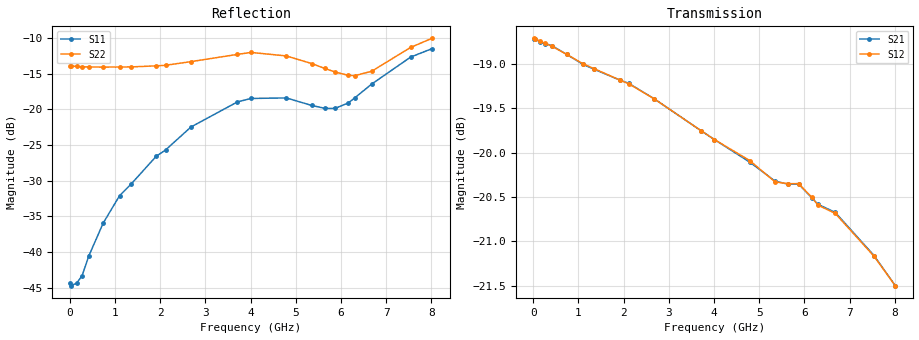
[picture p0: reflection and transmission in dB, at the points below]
! DEVICE ID: PE43712
! File Path: z:\PE43713\PE43713_CHAR_NOM_04292014\AMB\3p300\LS_ATT_17p50dB\PE43713_AMB_3p300V_3p000V_0p000V_LS_ATT_17p50dB_S2P_SN_10_A0139A.s2p
! Serial: 10
! Lot: A0139A
! Temp: 25C
! VDD: 3.300
! VSS: 0.000
! Control_Hi: 3.000
! Control_Lo: 0.000
! Attenuation Step: 17.50dB
! Port 1: RF1
! Port 2: RF2
! ThroughPath:1-2
! IDD: 0.0001465933
! ISS: -1.47e-007
#  Hz  S  RI  R  50
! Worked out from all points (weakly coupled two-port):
!   801 points, 10 MHz to 8.01 GHz, reference 50 ohm
!   highest |S21| = -18.71 dB at 10 MHz (marker M1); lowest = -21.5 dB at 8.01 GHz (marker M2)
!   lowest |S11| = -44.7 dB at 30 MHz (marker M3), VSWR 1.01, Z = 49.4 + j0.136 ohm
!   |S11| at or under -10 dB: start of sweep to end of sweep
!   |S22| runs from -15.3 to -10.0 dB; largest |S21 - S12| = 0.00042
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1e7  -0.00601 0.000558  0.1159 -0.00059  0.116 -0.000561  -0.2019 0.00137
3e7  -0.00564 0.00137  0.1159 -0.00145  0.1159 -0.00147  -0.2013 0.00327
1.5e8  -0.00479 0.0037  0.1153 -0.00683  0.1154 -0.00684  -0.1997 0.0125
2.7e8  -0.0041 0.00542  0.1146 -0.012  0.1146 -0.0121  -0.1981 0.0202
4.2e8  -0.00377 0.00859  0.1134 -0.0184  0.1133 -0.0184  -0.1961 0.0302
7.4e8  -0.00348 0.0156  0.1093 -0.031  0.1093 -0.031  -0.1907 0.0532
1.1e9  -0.00215 0.0247  0.1032 -0.0439  0.1033 -0.0439  -0.1823 0.0781
1.35e9  0.000228 0.0298  0.0985 -0.0521  0.0986 -0.0521  -0.1751 0.0935
1.91e9  0.00883 0.046  0.0857 -0.0688  0.0857 -0.0688  -0.1527 0.1322
2.12e9  0.0128 0.0504  0.0802 -0.0744  0.0802 -0.0743  -0.1444 0.144
2.68e9  0.0268 0.0703  0.0635 -0.0864  0.0635 -0.0864  -0.1126 0.1846
3.71e9  0.0389 0.106  0.0291 -0.0987  0.0291 -0.0987  -0.073 0.2319
4.01e9  0.04 0.1124  0.0191 -0.0999  0.0191 -0.0999  -0.0674 0.2416
4.79e9  0.0435 0.1122  -0.00582 -0.0986  -0.00581 -0.0988  -0.0414 0.2334
5.35e9  0.0559 0.0908  -0.0221 -0.0938  -0.0221 -0.0937  -0.0164 0.2091
5.64e9  0.0666 0.0769  -0.0299 -0.0912  -0.0298 -0.0913  0.00754 0.1937
5.87e9  0.0767 0.0666  -0.0372 -0.0885  -0.0371 -0.0886  0.0305 0.1802
6.16e9  0.0943 0.0585  -0.0457 -0.0825  -0.0455 -0.0827  0.0647 0.1608
6.3e9  0.1066 0.0554  -0.0484 -0.08  -0.0482 -0.08  0.0837 0.1505
6.68e9  0.1413 0.052  -0.057 -0.0729  -0.0568 -0.0729  0.1338 0.128
7.54e9  0.2242 0.0618  -0.072 -0.0497  -0.0719 -0.0497  0.2436 0.1209
8.01e9  0.2553 0.0762  -0.075 -0.0381  -0.0749 -0.0383  0.2892 0.1244
